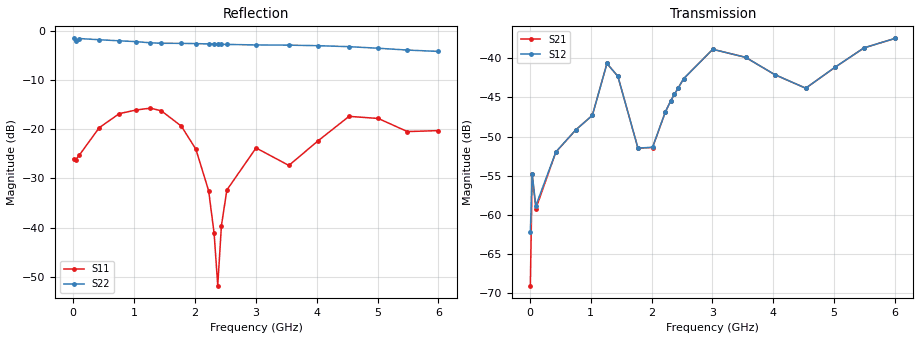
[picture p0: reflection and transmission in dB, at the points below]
!Agilent Technologies,E8364B,MY43040528,A.07.50.67
!Agilent E8364B: A.07.50.67
!Date: Sunday, September 28, 2025 22:30:23
!Correction: S11(Full 2 Port(1,2))
!S21(Full 2 Port(1,2))
!S12(Full 2 Port(1,2))
!S22(Full 2 Port(1,2))
!S2P File: Measurements: S11, S21, S12, S22:
# Hz S  dB  R 50
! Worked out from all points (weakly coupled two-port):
!   201 points, 10 MHz to 6 GHz, reference 50 ohm
!   highest |S21| = -37.46 dB at 6 GHz (marker M1); lowest = -69.1 dB at 10 MHz (marker M2)
!   lowest |S11| = -51.8 dB at 2.376 GHz (marker M3), VSWR 1.01, Z = 49.8 + j0.191 ohm
!   |S11| at or under -10 dB: start of sweep to end of sweep
!   |S22| runs from -4.2 to -1.5 dB; largest |S21 - S12| = 0.00082
!   S11 on the Smith chart (normalised r, x): 10 MHz: 1.09, -0.05; 758.8 MHz: 0.76, -0.08; 1.448 GHz: 0.85, +0.25; 6 GHz: 1.19, -0.09
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1e7  -26.08 -25.2  -69.07 108.6  -62.18 24.3  -1.51 179.9
3.995e7  -26.22 -15.8  -54.84 22.3  -54.76 23.6  -2.08 -175.8
9.985e7  -25.32 -30.5  -59.24 23.3  -58.85 23.2  -1.54 169.8
4.293e8  -19.69 -106.9  -51.99 4.0  -51.96 3.8  -1.79 129.7
7.5875e8  -16.83 -158.8  -49.13 -38.8  -49.13 -38.5  -2.01 91.6
1.0283e9  -16.10 167.1  -47.29 -63.7  -47.30 -63.5  -2.17 60.0
1.2679e9  -15.71 137.2  -40.66 -116.8  -40.66 -116.7  -2.41 31.8
1.4476e9  -16.24 112.6  -42.31 171.2  -42.30 171.3  -2.51 11.4
1.77705e9  -19.36 70.0  -51.48 82.5  -51.48 82.4  -2.52 -28.3
2.01665e9  -24.06 40.3  -51.41 -6.4  -51.37 -6.5  -2.58 -58.0
2.2263e9  -32.52 20.0  -46.89 -74.5  -46.87 -74.3  -2.64 -84.1
2.31615e9  -41.17 14.7  -45.41 -97.3  -45.42 -97.1  -2.66 -95.3
2.37605e9  -51.84 131.6  -44.60 -110.7  -44.60 -110.5  -2.68 -102.6
2.43595e9  -39.65 164.9  -43.83 -122.9  -43.82 -122.8  -2.70 -110.1
2.5258e9  -32.37 159.0  -42.62 -140.1  -42.62 -139.9  -2.74 -121.1
3.005e9  -23.81 111.1  -38.85 123.2  -38.85 123.3  -2.85 -178.0
3.5441e9  -27.37 81.3  -39.87 37.5  -39.87 37.6  -2.89 119.9
4.0233e9  -22.36 109.8  -42.09 -26.3  -42.08 -26.3  -3.00 66.6
4.53245e9  -17.38 66.3  -43.82 -63.8  -43.82 -63.6  -3.20 10.6
5.01165e9  -17.81 23.2  -41.16 -108.3  -41.15 -108.1  -3.52 -44.6
5.49085e9  -20.48 1.7  -38.66 -169.9  -38.66 -169.7  -3.89 -103.9
6e9  -20.28 -22.1  -37.46 115.1  -37.45 115.3  -4.17 -170.6
